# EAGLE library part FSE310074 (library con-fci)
48 ways CMC Male header 17464807 Powertrain 48 I/O Connector system sealed ECU Four rows (40x0.64) + (8x1.5) Source: Data sheet

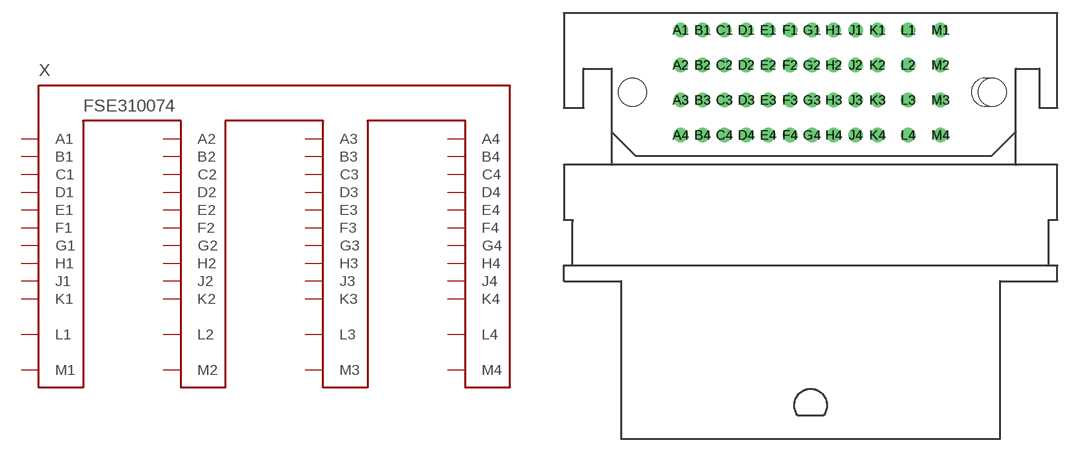
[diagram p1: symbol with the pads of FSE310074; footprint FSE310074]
Designator prefix X

## FSE310074  [FSE310074]
A1  A1  pas
A2  A2  pas
A3  A3  pas
A4  A4  pas
B1  B1  pas
B2  B2  pas
B3  B3  pas
B4  B4  pas
C1  C1  pas
C2  C2  pas
C3  C3  pas
C4  C4  pas
D1  D1  pas
D2  D2  pas
D3  D3  pas
D4  D4  pas
E1  E1  pas
E2  E2  pas
E3  E3  pas
E4  E4  pas
F1  F1  pas
F2  F2  pas
F3  F3  pas
F4  F4  pas
G1  G1  pas
G2  G2  pas
G3  G3  pas
G4  G4  pas
H1  H1  pas
H2  H2  pas
H3  H3  pas
H4  H4  pas
J1  J1  pas
J2  J2  pas
J3  J3  pas
J4  J4  pas
K1  K1  pas
K2  K2  pas
K3  K3  pas
K4  K4  pas
L1  L1  pas
L2  L2  pas
L3  L3  pas
L4  L4  pas
M1  M1  pas
M2  M2  pas
M3  M3  pas
M4  M4  pas

## Footprint FSE310074 (pad centres in mm)
48 ways CMC Male header 17464807 Powertrain 48 I/O Connector system sealed ECU Four rows (40x0.64) + (8x1.5) Source: Data sheet
drill 1.1 pad 1.5: A1 -14.85,12; A2 -14.85,8; A3 -14.85,4; A4 -14.85,0; B1 -12.35,12; B2 -12.35,8; B3 -12.35,4; B4 -12.35,0; C1 -9.85,12; C2 -9.85,8; C3 -9.85,4; C4 -9.85,0; D1 -7.35,12; D2 -7.35,8; D3 -7.35,4; D4 -7.35,0; E1 -4.85,12; E2 -4.85,8; E3 -4.85,4; E4 -4.85,0; F1 -2.35,12; F2 -2.35,8; F3 -2.35,4; F4 -2.35,0; G1 0.15,12; G2 0.15,8; G3 0.15,4; G4 0.15,0; H1 2.65,12; H2 2.65,8; H3 2.65,4; H4 2.65,0; J1 5.15,12; J2 5.15,8; J3 5.15,4; J4 5.15,0; K1 7.65,12; K2 7.65,8; K3 7.65,4; K4 7.65,0; L1 11.15,12; L2 11.15,8; L3 11.15,4; L4 11.15,0; M1 14.85,12; M2 14.85,8; M3 14.85,4; M4 14.85,0
hole 3.2 at -20.35,4.9
hole 3.2 at 20.75,4.9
